VERSION 5.7 ;
  NOWIREEXTENSIONATPIN ON ;
  DIVIDERCHAR "/" ;
  BUSBITCHARS "[]" ;
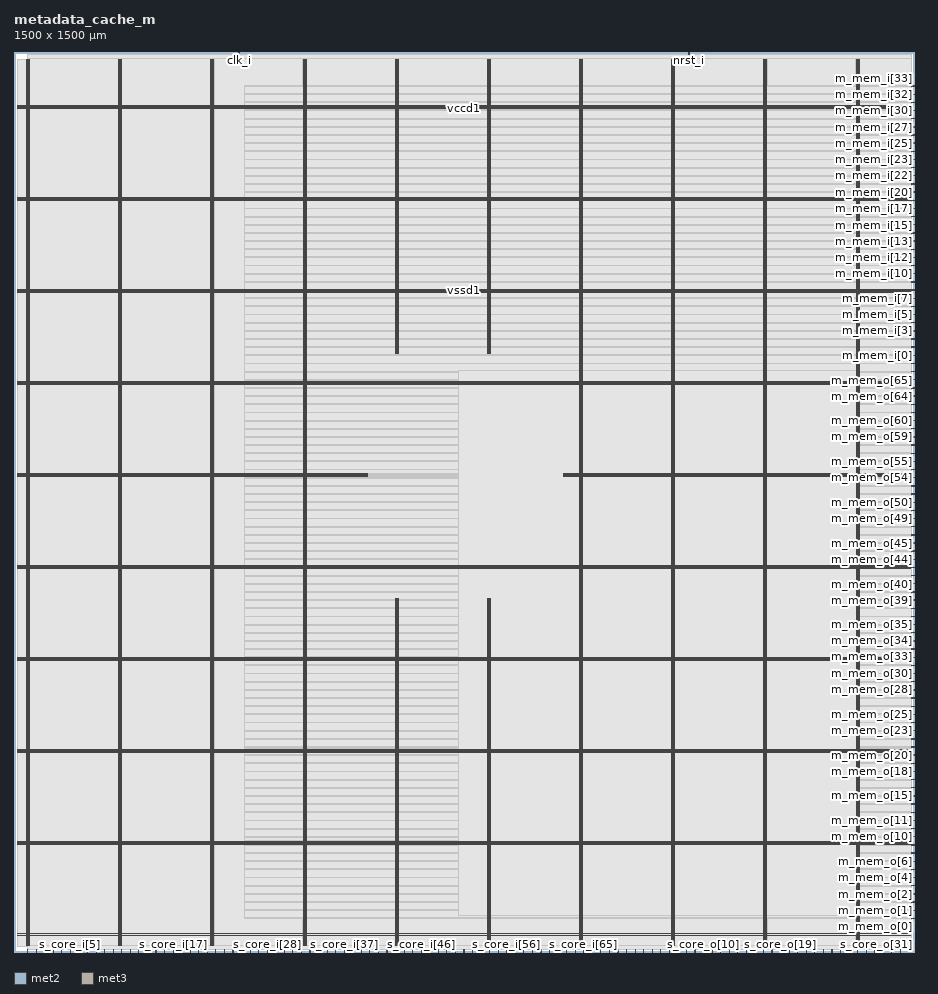
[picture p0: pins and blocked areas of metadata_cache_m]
MACRO metadata_cache_m
  CLASS BLOCK ;
  FOREIGN metadata_cache_m ;
  ORIGIN 0.000 0.000 ;
  SIZE 1500.000 BY 1500.000 ;
  PIN clk_i
    DIRECTION INPUT ;
    USE SIGNAL ;
    ANTENNAGATEAREA 0.990000 ;
    PORT
      LAYER met2 ;
        RECT 374.990 1496.000 375.270 1500.000 ;
    END
  END clk_i
  PIN m_mem_i[0]
    DIRECTION INPUT ;
    USE SIGNAL ;
    ANTENNAGATEAREA 0.742500 ;
    PORT
      LAYER met3 ;
        RECT 1496.000 994.200 1500.000 994.800 ;
    END
  END m_mem_i[0]
  PIN m_mem_i[10]
    DIRECTION INPUT ;
    USE SIGNAL ;
    ANTENNAGATEAREA 0.852000 ;
    PORT
      LAYER met3 ;
        RECT 1496.000 1130.200 1500.000 1130.800 ;
    END
  END m_mem_i[10]
  PIN m_mem_i[11]
    DIRECTION INPUT ;
    USE SIGNAL ;
    ANTENNAGATEAREA 0.990000 ;
    PORT
      LAYER met3 ;
        RECT 1496.000 1143.800 1500.000 1144.400 ;
    END
  END m_mem_i[11]
  PIN m_mem_i[12]
    DIRECTION INPUT ;
    USE SIGNAL ;
    ANTENNAGATEAREA 0.990000 ;
    PORT
      LAYER met3 ;
        RECT 1496.000 1157.400 1500.000 1158.000 ;
    END
  END m_mem_i[12]
  PIN m_mem_i[13]
    DIRECTION INPUT ;
    USE SIGNAL ;
    ANTENNAGATEAREA 0.990000 ;
    PORT
      LAYER met3 ;
        RECT 1496.000 1171.000 1500.000 1171.600 ;
    END
  END m_mem_i[13]
  PIN m_mem_i[14]
    DIRECTION INPUT ;
    USE SIGNAL ;
    ANTENNAGATEAREA 0.990000 ;
    PORT
      LAYER met3 ;
        RECT 1496.000 1184.600 1500.000 1185.200 ;
    END
  END m_mem_i[14]
  PIN m_mem_i[15]
    DIRECTION INPUT ;
    USE SIGNAL ;
    ANTENNAGATEAREA 0.990000 ;
    PORT
      LAYER met3 ;
        RECT 1496.000 1198.200 1500.000 1198.800 ;
    END
  END m_mem_i[15]
  PIN m_mem_i[16]
    DIRECTION INPUT ;
    USE SIGNAL ;
    ANTENNAGATEAREA 0.852000 ;
    PORT
      LAYER met3 ;
        RECT 1496.000 1211.800 1500.000 1212.400 ;
    END
  END m_mem_i[16]
  PIN m_mem_i[17]
    DIRECTION INPUT ;
    USE SIGNAL ;
    ANTENNAGATEAREA 0.742500 ;
    PORT
      LAYER met3 ;
        RECT 1496.000 1225.400 1500.000 1226.000 ;
    END
  END m_mem_i[17]
  PIN m_mem_i[18]
    DIRECTION INPUT ;
    USE SIGNAL ;
    ANTENNAGATEAREA 0.742500 ;
    PORT
      LAYER met3 ;
        RECT 1496.000 1239.000 1500.000 1239.600 ;
    END
  END m_mem_i[18]
  PIN m_mem_i[19]
    DIRECTION INPUT ;
    USE SIGNAL ;
    ANTENNAGATEAREA 0.742500 ;
    PORT
      LAYER met3 ;
        RECT 1496.000 1252.600 1500.000 1253.200 ;
    END
  END m_mem_i[19]
  PIN m_mem_i[1]
    DIRECTION INPUT ;
    USE SIGNAL ;
    ANTENNAGATEAREA 0.742500 ;
    PORT
      LAYER met3 ;
        RECT 1496.000 1007.800 1500.000 1008.400 ;
    END
  END m_mem_i[1]
  PIN m_mem_i[20]
    DIRECTION INPUT ;
    USE SIGNAL ;
    ANTENNAGATEAREA 0.742500 ;
    PORT
      LAYER met3 ;
        RECT 1496.000 1266.200 1500.000 1266.800 ;
    END
  END m_mem_i[20]
  PIN m_mem_i[21]
    DIRECTION INPUT ;
    USE SIGNAL ;
    ANTENNAGATEAREA 0.742500 ;
    PORT
      LAYER met3 ;
        RECT 1496.000 1279.800 1500.000 1280.400 ;
    END
  END m_mem_i[21]
  PIN m_mem_i[22]
    DIRECTION INPUT ;
    USE SIGNAL ;
    ANTENNAGATEAREA 0.742500 ;
    PORT
      LAYER met3 ;
        RECT 1496.000 1293.400 1500.000 1294.000 ;
    END
  END m_mem_i[22]
  PIN m_mem_i[23]
    DIRECTION INPUT ;
    USE SIGNAL ;
    ANTENNAGATEAREA 0.742500 ;
    PORT
      LAYER met3 ;
        RECT 1496.000 1307.000 1500.000 1307.600 ;
    END
  END m_mem_i[23]
  PIN m_mem_i[24]
    DIRECTION INPUT ;
    USE SIGNAL ;
    ANTENNAGATEAREA 0.852000 ;
    PORT
      LAYER met3 ;
        RECT 1496.000 1320.600 1500.000 1321.200 ;
    END
  END m_mem_i[24]
  PIN m_mem_i[25]
    DIRECTION INPUT ;
    USE SIGNAL ;
    ANTENNAGATEAREA 0.742500 ;
    PORT
      LAYER met3 ;
        RECT 1496.000 1334.200 1500.000 1334.800 ;
    END
  END m_mem_i[25]
  PIN m_mem_i[26]
    DIRECTION INPUT ;
    USE SIGNAL ;
    ANTENNAGATEAREA 0.742500 ;
    PORT
      LAYER met3 ;
        RECT 1496.000 1347.800 1500.000 1348.400 ;
    END
  END m_mem_i[26]
  PIN m_mem_i[27]
    DIRECTION INPUT ;
    USE SIGNAL ;
    ANTENNAGATEAREA 0.990000 ;
    PORT
      LAYER met3 ;
        RECT 1496.000 1361.400 1500.000 1362.000 ;
    END
  END m_mem_i[27]
  PIN m_mem_i[28]
    DIRECTION INPUT ;
    USE SIGNAL ;
    ANTENNAGATEAREA 0.852000 ;
    PORT
      LAYER met3 ;
        RECT 1496.000 1375.000 1500.000 1375.600 ;
    END
  END m_mem_i[28]
  PIN m_mem_i[29]
    DIRECTION INPUT ;
    USE SIGNAL ;
    ANTENNAGATEAREA 0.852000 ;
    PORT
      LAYER met3 ;
        RECT 1496.000 1388.600 1500.000 1389.200 ;
    END
  END m_mem_i[29]
  PIN m_mem_i[2]
    DIRECTION INPUT ;
    USE SIGNAL ;
    ANTENNAGATEAREA 0.742500 ;
    PORT
      LAYER met3 ;
        RECT 1496.000 1021.400 1500.000 1022.000 ;
    END
  END m_mem_i[2]
  PIN m_mem_i[30]
    DIRECTION INPUT ;
    USE SIGNAL ;
    ANTENNAGATEAREA 0.852000 ;
    PORT
      LAYER met3 ;
        RECT 1496.000 1402.200 1500.000 1402.800 ;
    END
  END m_mem_i[30]
  PIN m_mem_i[31]
    DIRECTION INPUT ;
    USE SIGNAL ;
    ANTENNAGATEAREA 0.852000 ;
    PORT
      LAYER met3 ;
        RECT 1496.000 1415.800 1500.000 1416.400 ;
    END
  END m_mem_i[31]
  PIN m_mem_i[32]
    DIRECTION INPUT ;
    USE SIGNAL ;
    ANTENNAGATEAREA 0.990000 ;
    PORT
      LAYER met3 ;
        RECT 1496.000 1429.400 1500.000 1430.000 ;
    END
  END m_mem_i[32]
  PIN m_mem_i[33]
    DIRECTION INPUT ;
    USE SIGNAL ;
    ANTENNAGATEAREA 0.990000 ;
    PORT
      LAYER met3 ;
        RECT 1496.000 1443.000 1500.000 1443.600 ;
    END
  END m_mem_i[33]
  PIN m_mem_i[3]
    DIRECTION INPUT ;
    USE SIGNAL ;
    ANTENNAGATEAREA 0.742500 ;
    PORT
      LAYER met3 ;
        RECT 1496.000 1035.000 1500.000 1035.600 ;
    END
  END m_mem_i[3]
  PIN m_mem_i[4]
    DIRECTION INPUT ;
    USE SIGNAL ;
    ANTENNAGATEAREA 0.742500 ;
    PORT
      LAYER met3 ;
        RECT 1496.000 1048.600 1500.000 1049.200 ;
    END
  END m_mem_i[4]
  PIN m_mem_i[5]
    DIRECTION INPUT ;
    USE SIGNAL ;
    ANTENNAGATEAREA 0.742500 ;
    PORT
      LAYER met3 ;
        RECT 1496.000 1062.200 1500.000 1062.800 ;
    END
  END m_mem_i[5]
  PIN m_mem_i[6]
    DIRECTION INPUT ;
    USE SIGNAL ;
    ANTENNAGATEAREA 0.742500 ;
    PORT
      LAYER met3 ;
        RECT 1496.000 1075.800 1500.000 1076.400 ;
    END
  END m_mem_i[6]
  PIN m_mem_i[7]
    DIRECTION INPUT ;
    USE SIGNAL ;
    ANTENNAGATEAREA 0.742500 ;
    PORT
      LAYER met3 ;
        RECT 1496.000 1089.400 1500.000 1090.000 ;
    END
  END m_mem_i[7]
  PIN m_mem_i[8]
    DIRECTION INPUT ;
    USE SIGNAL ;
    ANTENNAGATEAREA 0.742500 ;
    PORT
      LAYER met3 ;
        RECT 1496.000 1103.000 1500.000 1103.600 ;
    END
  END m_mem_i[8]
  PIN m_mem_i[9]
    DIRECTION INPUT ;
    USE SIGNAL ;
    ANTENNAGATEAREA 0.852000 ;
    PORT
      LAYER met3 ;
        RECT 1496.000 1116.600 1500.000 1117.200 ;
    END
  END m_mem_i[9]
  PIN m_mem_o[0]
    DIRECTION OUTPUT TRISTATE ;
    USE SIGNAL ;
    ANTENNADIFFAREA 2.673000 ;
    PORT
      LAYER met3 ;
        RECT 1496.000 55.800 1500.000 56.400 ;
    END
  END m_mem_o[0]
  PIN m_mem_o[10]
    DIRECTION OUTPUT TRISTATE ;
    USE SIGNAL ;
    ANTENNADIFFAREA 2.673000 ;
    PORT
      LAYER met3 ;
        RECT 1496.000 191.800 1500.000 192.400 ;
    END
  END m_mem_o[10]
  PIN m_mem_o[11]
    DIRECTION OUTPUT TRISTATE ;
    USE SIGNAL ;
    ANTENNADIFFAREA 2.673000 ;
    PORT
      LAYER met3 ;
        RECT 1496.000 205.400 1500.000 206.000 ;
    END
  END m_mem_o[11]
  PIN m_mem_o[12]
    DIRECTION OUTPUT TRISTATE ;
    USE SIGNAL ;
    ANTENNADIFFAREA 2.673000 ;
    PORT
      LAYER met3 ;
        RECT 1496.000 219.000 1500.000 219.600 ;
    END
  END m_mem_o[12]
  PIN m_mem_o[13]
    DIRECTION OUTPUT TRISTATE ;
    USE SIGNAL ;
    ANTENNADIFFAREA 2.673000 ;
    PORT
      LAYER met3 ;
        RECT 1496.000 232.600 1500.000 233.200 ;
    END
  END m_mem_o[13]
  PIN m_mem_o[14]
    DIRECTION OUTPUT TRISTATE ;
    USE SIGNAL ;
    ANTENNADIFFAREA 2.673000 ;
    PORT
      LAYER met3 ;
        RECT 1496.000 246.200 1500.000 246.800 ;
    END
  END m_mem_o[14]
  PIN m_mem_o[15]
    DIRECTION OUTPUT TRISTATE ;
    USE SIGNAL ;
    ANTENNADIFFAREA 2.673000 ;
    PORT
      LAYER met3 ;
        RECT 1496.000 259.800 1500.000 260.400 ;
    END
  END m_mem_o[15]
  PIN m_mem_o[16]
    DIRECTION OUTPUT TRISTATE ;
    USE SIGNAL ;
    ANTENNADIFFAREA 2.673000 ;
    PORT
      LAYER met3 ;
        RECT 1496.000 273.400 1500.000 274.000 ;
    END
  END m_mem_o[16]
  PIN m_mem_o[17]
    DIRECTION OUTPUT TRISTATE ;
    USE SIGNAL ;
    ANTENNADIFFAREA 2.673000 ;
    PORT
      LAYER met3 ;
        RECT 1496.000 287.000 1500.000 287.600 ;
    END
  END m_mem_o[17]
  PIN m_mem_o[18]
    DIRECTION OUTPUT TRISTATE ;
    USE SIGNAL ;
    ANTENNADIFFAREA 2.673000 ;
    PORT
      LAYER met3 ;
        RECT 1496.000 300.600 1500.000 301.200 ;
    END
  END m_mem_o[18]
  PIN m_mem_o[19]
    DIRECTION OUTPUT TRISTATE ;
    USE SIGNAL ;
    ANTENNADIFFAREA 2.673000 ;
    PORT
      LAYER met3 ;
        RECT 1496.000 314.200 1500.000 314.800 ;
    END
  END m_mem_o[19]
  PIN m_mem_o[1]
    DIRECTION OUTPUT TRISTATE ;
    USE SIGNAL ;
    ANTENNADIFFAREA 2.673000 ;
    PORT
      LAYER met3 ;
        RECT 1496.000 69.400 1500.000 70.000 ;
    END
  END m_mem_o[1]
  PIN m_mem_o[20]
    DIRECTION OUTPUT TRISTATE ;
    USE SIGNAL ;
    ANTENNADIFFAREA 2.673000 ;
    PORT
      LAYER met3 ;
        RECT 1496.000 327.800 1500.000 328.400 ;
    END
  END m_mem_o[20]
  PIN m_mem_o[21]
    DIRECTION OUTPUT TRISTATE ;
    USE SIGNAL ;
    ANTENNADIFFAREA 2.673000 ;
    PORT
      LAYER met3 ;
        RECT 1496.000 341.400 1500.000 342.000 ;
    END
  END m_mem_o[21]
  PIN m_mem_o[22]
    DIRECTION OUTPUT TRISTATE ;
    USE SIGNAL ;
    ANTENNADIFFAREA 2.673000 ;
    PORT
      LAYER met3 ;
        RECT 1496.000 355.000 1500.000 355.600 ;
    END
  END m_mem_o[22]
  PIN m_mem_o[23]
    DIRECTION OUTPUT TRISTATE ;
    USE SIGNAL ;
    ANTENNADIFFAREA 2.673000 ;
    PORT
      LAYER met3 ;
        RECT 1496.000 368.600 1500.000 369.200 ;
    END
  END m_mem_o[23]
  PIN m_mem_o[24]
    DIRECTION OUTPUT TRISTATE ;
    USE SIGNAL ;
    ANTENNADIFFAREA 2.673000 ;
    PORT
      LAYER met3 ;
        RECT 1496.000 382.200 1500.000 382.800 ;
    END
  END m_mem_o[24]
  PIN m_mem_o[25]
    DIRECTION OUTPUT TRISTATE ;
    USE SIGNAL ;
    ANTENNADIFFAREA 2.673000 ;
    PORT
      LAYER met3 ;
        RECT 1496.000 395.800 1500.000 396.400 ;
    END
  END m_mem_o[25]
  PIN m_mem_o[26]
    DIRECTION OUTPUT TRISTATE ;
    USE SIGNAL ;
    ANTENNADIFFAREA 2.673000 ;
    PORT
      LAYER met3 ;
        RECT 1496.000 409.400 1500.000 410.000 ;
    END
  END m_mem_o[26]
  PIN m_mem_o[27]
    DIRECTION OUTPUT TRISTATE ;
    USE SIGNAL ;
    ANTENNADIFFAREA 2.673000 ;
    PORT
      LAYER met3 ;
        RECT 1496.000 423.000 1500.000 423.600 ;
    END
  END m_mem_o[27]
  PIN m_mem_o[28]
    DIRECTION OUTPUT TRISTATE ;
    USE SIGNAL ;
    ANTENNADIFFAREA 2.673000 ;
    PORT
      LAYER met3 ;
        RECT 1496.000 436.600 1500.000 437.200 ;
    END
  END m_mem_o[28]
  PIN m_mem_o[29]
    DIRECTION OUTPUT TRISTATE ;
    USE SIGNAL ;
    ANTENNADIFFAREA 2.673000 ;
    PORT
      LAYER met3 ;
        RECT 1496.000 450.200 1500.000 450.800 ;
    END
  END m_mem_o[29]
  PIN m_mem_o[2]
    DIRECTION OUTPUT TRISTATE ;
    USE SIGNAL ;
    ANTENNADIFFAREA 2.673000 ;
    PORT
      LAYER met3 ;
        RECT 1496.000 83.000 1500.000 83.600 ;
    END
  END m_mem_o[2]
  PIN m_mem_o[30]
    DIRECTION OUTPUT TRISTATE ;
    USE SIGNAL ;
    ANTENNADIFFAREA 2.673000 ;
    PORT
      LAYER met3 ;
        RECT 1496.000 463.800 1500.000 464.400 ;
    END
  END m_mem_o[30]
  PIN m_mem_o[31]
    DIRECTION OUTPUT TRISTATE ;
    USE SIGNAL ;
    ANTENNADIFFAREA 2.673000 ;
    PORT
      LAYER met3 ;
        RECT 1496.000 477.400 1500.000 478.000 ;
    END
  END m_mem_o[31]
  PIN m_mem_o[32]
    DIRECTION OUTPUT TRISTATE ;
    USE SIGNAL ;
    PORT
      LAYER met3 ;
        RECT 1496.000 491.000 1500.000 491.600 ;
    END
  END m_mem_o[32]
  PIN m_mem_o[33]
    DIRECTION OUTPUT TRISTATE ;
    USE SIGNAL ;
    PORT
      LAYER met3 ;
        RECT 1496.000 504.600 1500.000 505.200 ;
    END
  END m_mem_o[33]
  PIN m_mem_o[34]
    DIRECTION OUTPUT TRISTATE ;
    USE SIGNAL ;
    PORT
      LAYER met3 ;
        RECT 1496.000 518.200 1500.000 518.800 ;
    END
  END m_mem_o[34]
  PIN m_mem_o[35]
    DIRECTION OUTPUT TRISTATE ;
    USE SIGNAL ;
    PORT
      LAYER met3 ;
        RECT 1496.000 531.800 1500.000 532.400 ;
    END
  END m_mem_o[35]
  PIN m_mem_o[36]
    DIRECTION OUTPUT TRISTATE ;
    USE SIGNAL ;
    PORT
      LAYER met3 ;
        RECT 1496.000 545.400 1500.000 546.000 ;
    END
  END m_mem_o[36]
  PIN m_mem_o[37]
    DIRECTION OUTPUT TRISTATE ;
    USE SIGNAL ;
    PORT
      LAYER met3 ;
        RECT 1496.000 559.000 1500.000 559.600 ;
    END
  END m_mem_o[37]
  PIN m_mem_o[38]
    DIRECTION OUTPUT TRISTATE ;
    USE SIGNAL ;
    ANTENNADIFFAREA 2.673000 ;
    PORT
      LAYER met3 ;
        RECT 1496.000 572.600 1500.000 573.200 ;
    END
  END m_mem_o[38]
  PIN m_mem_o[39]
    DIRECTION OUTPUT TRISTATE ;
    USE SIGNAL ;
    ANTENNADIFFAREA 2.673000 ;
    PORT
      LAYER met3 ;
        RECT 1496.000 586.200 1500.000 586.800 ;
    END
  END m_mem_o[39]
  PIN m_mem_o[3]
    DIRECTION OUTPUT TRISTATE ;
    USE SIGNAL ;
    ANTENNADIFFAREA 2.673000 ;
    PORT
      LAYER met3 ;
        RECT 1496.000 96.600 1500.000 97.200 ;
    END
  END m_mem_o[3]
  PIN m_mem_o[40]
    DIRECTION OUTPUT TRISTATE ;
    USE SIGNAL ;
    ANTENNADIFFAREA 2.673000 ;
    PORT
      LAYER met3 ;
        RECT 1496.000 599.800 1500.000 600.400 ;
    END
  END m_mem_o[40]
  PIN m_mem_o[41]
    DIRECTION OUTPUT TRISTATE ;
    USE SIGNAL ;
    ANTENNADIFFAREA 2.673000 ;
    PORT
      LAYER met3 ;
        RECT 1496.000 613.400 1500.000 614.000 ;
    END
  END m_mem_o[41]
  PIN m_mem_o[42]
    DIRECTION OUTPUT TRISTATE ;
    USE SIGNAL ;
    ANTENNADIFFAREA 2.673000 ;
    PORT
      LAYER met3 ;
        RECT 1496.000 627.000 1500.000 627.600 ;
    END
  END m_mem_o[42]
  PIN m_mem_o[43]
    DIRECTION OUTPUT TRISTATE ;
    USE SIGNAL ;
    ANTENNADIFFAREA 2.673000 ;
    PORT
      LAYER met3 ;
        RECT 1496.000 640.600 1500.000 641.200 ;
    END
  END m_mem_o[43]
  PIN m_mem_o[44]
    DIRECTION OUTPUT TRISTATE ;
    USE SIGNAL ;
    ANTENNADIFFAREA 2.673000 ;
    PORT
      LAYER met3 ;
        RECT 1496.000 654.200 1500.000 654.800 ;
    END
  END m_mem_o[44]
  PIN m_mem_o[45]
    DIRECTION OUTPUT TRISTATE ;
    USE SIGNAL ;
    ANTENNADIFFAREA 2.673000 ;
    PORT
      LAYER met3 ;
        RECT 1496.000 667.800 1500.000 668.400 ;
    END
  END m_mem_o[45]
  PIN m_mem_o[46]
    DIRECTION OUTPUT TRISTATE ;
    USE SIGNAL ;
    ANTENNADIFFAREA 2.673000 ;
    PORT
      LAYER met3 ;
        RECT 1496.000 681.400 1500.000 682.000 ;
    END
  END m_mem_o[46]
  PIN m_mem_o[47]
    DIRECTION OUTPUT TRISTATE ;
    USE SIGNAL ;
    ANTENNADIFFAREA 2.673000 ;
    PORT
      LAYER met3 ;
        RECT 1496.000 695.000 1500.000 695.600 ;
    END
  END m_mem_o[47]
  PIN m_mem_o[48]
    DIRECTION OUTPUT TRISTATE ;
    USE SIGNAL ;
    ANTENNADIFFAREA 2.673000 ;
    PORT
      LAYER met3 ;
        RECT 1496.000 708.600 1500.000 709.200 ;
    END
  END m_mem_o[48]
  PIN m_mem_o[49]
    DIRECTION OUTPUT TRISTATE ;
    USE SIGNAL ;
    ANTENNADIFFAREA 2.673000 ;
    PORT
      LAYER met3 ;
        RECT 1496.000 722.200 1500.000 722.800 ;
    END
  END m_mem_o[49]
  PIN m_mem_o[4]
    DIRECTION OUTPUT TRISTATE ;
    USE SIGNAL ;
    ANTENNADIFFAREA 2.673000 ;
    PORT
      LAYER met3 ;
        RECT 1496.000 110.200 1500.000 110.800 ;
    END
  END m_mem_o[4]
  PIN m_mem_o[50]
    DIRECTION OUTPUT TRISTATE ;
    USE SIGNAL ;
    ANTENNADIFFAREA 2.673000 ;
    PORT
      LAYER met3 ;
        RECT 1496.000 735.800 1500.000 736.400 ;
    END
  END m_mem_o[50]
  PIN m_mem_o[51]
    DIRECTION OUTPUT TRISTATE ;
    USE SIGNAL ;
    ANTENNADIFFAREA 2.673000 ;
    PORT
      LAYER met3 ;
        RECT 1496.000 749.400 1500.000 750.000 ;
    END
  END m_mem_o[51]
  PIN m_mem_o[52]
    DIRECTION OUTPUT TRISTATE ;
    USE SIGNAL ;
    ANTENNADIFFAREA 2.673000 ;
    PORT
      LAYER met3 ;
        RECT 1496.000 763.000 1500.000 763.600 ;
    END
  END m_mem_o[52]
  PIN m_mem_o[53]
    DIRECTION OUTPUT TRISTATE ;
    USE SIGNAL ;
    ANTENNADIFFAREA 2.673000 ;
    PORT
      LAYER met3 ;
        RECT 1496.000 776.600 1500.000 777.200 ;
    END
  END m_mem_o[53]
  PIN m_mem_o[54]
    DIRECTION OUTPUT TRISTATE ;
    USE SIGNAL ;
    ANTENNADIFFAREA 2.673000 ;
    PORT
      LAYER met3 ;
        RECT 1496.000 790.200 1500.000 790.800 ;
    END
  END m_mem_o[54]
  PIN m_mem_o[55]
    DIRECTION OUTPUT TRISTATE ;
    USE SIGNAL ;
    ANTENNADIFFAREA 2.673000 ;
    PORT
      LAYER met3 ;
        RECT 1496.000 803.800 1500.000 804.400 ;
    END
  END m_mem_o[55]
  PIN m_mem_o[56]
    DIRECTION OUTPUT TRISTATE ;
    USE SIGNAL ;
    ANTENNADIFFAREA 2.673000 ;
    PORT
      LAYER met3 ;
        RECT 1496.000 817.400 1500.000 818.000 ;
    END
  END m_mem_o[56]
  PIN m_mem_o[57]
    DIRECTION OUTPUT TRISTATE ;
    USE SIGNAL ;
    ANTENNADIFFAREA 2.673000 ;
    PORT
      LAYER met3 ;
        RECT 1496.000 831.000 1500.000 831.600 ;
    END
  END m_mem_o[57]
  PIN m_mem_o[58]
    DIRECTION OUTPUT TRISTATE ;
    USE SIGNAL ;
    ANTENNADIFFAREA 2.673000 ;
    PORT
      LAYER met3 ;
        RECT 1496.000 844.600 1500.000 845.200 ;
    END
  END m_mem_o[58]
  PIN m_mem_o[59]
    DIRECTION OUTPUT TRISTATE ;
    USE SIGNAL ;
    ANTENNADIFFAREA 2.673000 ;
    PORT
      LAYER met3 ;
        RECT 1496.000 858.200 1500.000 858.800 ;
    END
  END m_mem_o[59]
  PIN m_mem_o[5]
    DIRECTION OUTPUT TRISTATE ;
    USE SIGNAL ;
    ANTENNADIFFAREA 2.673000 ;
    PORT
      LAYER met3 ;
        RECT 1496.000 123.800 1500.000 124.400 ;
    END
  END m_mem_o[5]
  PIN m_mem_o[60]
    DIRECTION OUTPUT TRISTATE ;
    USE SIGNAL ;
    ANTENNADIFFAREA 2.673000 ;
    PORT
      LAYER met3 ;
        RECT 1496.000 871.800 1500.000 872.400 ;
    END
  END m_mem_o[60]
  PIN m_mem_o[61]
    DIRECTION OUTPUT TRISTATE ;
    USE SIGNAL ;
    ANTENNADIFFAREA 2.673000 ;
    PORT
      LAYER met3 ;
        RECT 1496.000 885.400 1500.000 886.000 ;
    END
  END m_mem_o[61]
  PIN m_mem_o[62]
    DIRECTION OUTPUT TRISTATE ;
    USE SIGNAL ;
    ANTENNADIFFAREA 2.673000 ;
    PORT
      LAYER met3 ;
        RECT 1496.000 899.000 1500.000 899.600 ;
    END
  END m_mem_o[62]
  PIN m_mem_o[63]
    DIRECTION OUTPUT TRISTATE ;
    USE SIGNAL ;
    ANTENNADIFFAREA 2.673000 ;
    PORT
      LAYER met3 ;
        RECT 1496.000 912.600 1500.000 913.200 ;
    END
  END m_mem_o[63]
  PIN m_mem_o[64]
    DIRECTION OUTPUT TRISTATE ;
    USE SIGNAL ;
    ANTENNADIFFAREA 2.673000 ;
    PORT
      LAYER met3 ;
        RECT 1496.000 926.200 1500.000 926.800 ;
    END
  END m_mem_o[64]
  PIN m_mem_o[65]
    DIRECTION OUTPUT TRISTATE ;
    USE SIGNAL ;
    ANTENNADIFFAREA 2.673000 ;
    PORT
      LAYER met3 ;
        RECT 1496.000 939.800 1500.000 940.400 ;
    END
  END m_mem_o[65]
  PIN m_mem_o[66]
    DIRECTION OUTPUT TRISTATE ;
    USE SIGNAL ;
    PORT
      LAYER met3 ;
        RECT 1496.000 953.400 1500.000 954.000 ;
    END
  END m_mem_o[66]
  PIN m_mem_o[67]
    DIRECTION OUTPUT TRISTATE ;
    USE SIGNAL ;
    PORT
      LAYER met3 ;
        RECT 1496.000 967.000 1500.000 967.600 ;
    END
  END m_mem_o[67]
  PIN m_mem_o[68]
    DIRECTION OUTPUT TRISTATE ;
    USE SIGNAL ;
    ANTENNADIFFAREA 2.673000 ;
    PORT
      LAYER met3 ;
        RECT 1496.000 980.600 1500.000 981.200 ;
    END
  END m_mem_o[68]
  PIN m_mem_o[6]
    DIRECTION OUTPUT TRISTATE ;
    USE SIGNAL ;
    ANTENNADIFFAREA 2.673000 ;
    PORT
      LAYER met3 ;
        RECT 1496.000 137.400 1500.000 138.000 ;
    END
  END m_mem_o[6]
  PIN m_mem_o[7]
    DIRECTION OUTPUT TRISTATE ;
    USE SIGNAL ;
    ANTENNADIFFAREA 2.673000 ;
    PORT
      LAYER met3 ;
        RECT 1496.000 151.000 1500.000 151.600 ;
    END
  END m_mem_o[7]
  PIN m_mem_o[8]
    DIRECTION OUTPUT TRISTATE ;
    USE SIGNAL ;
    ANTENNADIFFAREA 2.673000 ;
    PORT
      LAYER met3 ;
        RECT 1496.000 164.600 1500.000 165.200 ;
    END
  END m_mem_o[8]
  PIN m_mem_o[9]
    DIRECTION OUTPUT TRISTATE ;
    USE SIGNAL ;
    ANTENNADIFFAREA 2.673000 ;
    PORT
      LAYER met3 ;
        RECT 1496.000 178.200 1500.000 178.800 ;
    END
  END m_mem_o[9]
  PIN nrst_i
    DIRECTION INPUT ;
    USE SIGNAL ;
    ANTENNAGATEAREA 0.990000 ;
    PORT
      LAYER met2 ;
        RECT 1124.790 1496.000 1125.070 1500.000 ;
    END
  END nrst_i
  PIN s_core_i[0]
    DIRECTION INPUT ;
    USE SIGNAL ;
    ANTENNAGATEAREA 0.742500 ;
    PORT
      LAYER met2 ;
        RECT 22.630 0.000 22.910 4.000 ;
    END
  END s_core_i[0]
  PIN s_core_i[10]
    DIRECTION INPUT ;
    USE SIGNAL ;
    ANTENNAGATEAREA 0.247500 ;
    PORT
      LAYER met2 ;
        RECT 165.230 0.000 165.510 4.000 ;
    END
  END s_core_i[10]
  PIN s_core_i[11]
    DIRECTION INPUT ;
    USE SIGNAL ;
    ANTENNAGATEAREA 0.247500 ;
    PORT
      LAYER met2 ;
        RECT 179.490 0.000 179.770 4.000 ;
    END
  END s_core_i[11]
  PIN s_core_i[12]
    DIRECTION INPUT ;
    USE SIGNAL ;
    ANTENNAGATEAREA 0.247500 ;
    PORT
      LAYER met2 ;
        RECT 193.750 0.000 194.030 4.000 ;
    END
  END s_core_i[12]
  PIN s_core_i[13]
    DIRECTION INPUT ;
    USE SIGNAL ;
    ANTENNAGATEAREA 0.247500 ;
    PORT
      LAYER met2 ;
        RECT 208.010 0.000 208.290 4.000 ;
    END
  END s_core_i[13]
  PIN s_core_i[14]
    DIRECTION INPUT ;
    USE SIGNAL ;
    ANTENNAGATEAREA 0.247500 ;
    PORT
      LAYER met2 ;
        RECT 222.270 0.000 222.550 4.000 ;
    END
  END s_core_i[14]
  PIN s_core_i[15]
    DIRECTION INPUT ;
    USE SIGNAL ;
    ANTENNAGATEAREA 0.247500 ;
    PORT
      LAYER met2 ;
        RECT 236.530 0.000 236.810 4.000 ;
    END
  END s_core_i[15]
  PIN s_core_i[16]
    DIRECTION INPUT ;
    USE SIGNAL ;
    ANTENNAGATEAREA 0.247500 ;
    PORT
      LAYER met2 ;
        RECT 250.790 0.000 251.070 4.000 ;
    END
  END s_core_i[16]
  PIN s_core_i[17]
    DIRECTION INPUT ;
    USE SIGNAL ;
    ANTENNAGATEAREA 0.247500 ;
    PORT
      LAYER met2 ;
        RECT 265.050 0.000 265.330 4.000 ;
    END
  END s_core_i[17]
  PIN s_core_i[18]
    DIRECTION INPUT ;
    USE SIGNAL ;
    ANTENNAGATEAREA 0.247500 ;
    PORT
      LAYER met2 ;
        RECT 279.310 0.000 279.590 4.000 ;
    END
  END s_core_i[18]
  PIN s_core_i[19]
    DIRECTION INPUT ;
    USE SIGNAL ;
    ANTENNAGATEAREA 0.247500 ;
    PORT
      LAYER met2 ;
        RECT 293.570 0.000 293.850 4.000 ;
    END
  END s_core_i[19]
  PIN s_core_i[1]
    DIRECTION INPUT ;
    USE SIGNAL ;
    ANTENNAGATEAREA 0.742500 ;
    PORT
      LAYER met2 ;
        RECT 36.890 0.000 37.170 4.000 ;
    END
  END s_core_i[1]
  PIN s_core_i[20]
    DIRECTION INPUT ;
    USE SIGNAL ;
    ANTENNAGATEAREA 0.247500 ;
    PORT
      LAYER met2 ;
        RECT 307.830 0.000 308.110 4.000 ;
    END
  END s_core_i[20]
  PIN s_core_i[21]
    DIRECTION INPUT ;
    USE SIGNAL ;
    ANTENNAGATEAREA 0.247500 ;
    PORT
      LAYER met2 ;
        RECT 322.090 0.000 322.370 4.000 ;
    END
  END s_core_i[21]
  PIN s_core_i[22]
    DIRECTION INPUT ;
    USE SIGNAL ;
    ANTENNAGATEAREA 0.247500 ;
    PORT
      LAYER met2 ;
        RECT 336.350 0.000 336.630 4.000 ;
    END
  END s_core_i[22]
  PIN s_core_i[23]
    DIRECTION INPUT ;
    USE SIGNAL ;
    ANTENNAGATEAREA 0.247500 ;
    PORT
      LAYER met2 ;
        RECT 350.610 0.000 350.890 4.000 ;
    END
  END s_core_i[23]
  PIN s_core_i[24]
    DIRECTION INPUT ;
    USE SIGNAL ;
    ANTENNAGATEAREA 0.213000 ;
    PORT
      LAYER met2 ;
        RECT 364.870 0.000 365.150 4.000 ;
    END
  END s_core_i[24]
  PIN s_core_i[25]
    DIRECTION INPUT ;
    USE SIGNAL ;
    ANTENNAGATEAREA 0.247500 ;
    PORT
      LAYER met2 ;
        RECT 379.130 0.000 379.410 4.000 ;
    END
  END s_core_i[25]
  PIN s_core_i[26]
    DIRECTION INPUT ;
    USE SIGNAL ;
    ANTENNAGATEAREA 0.247500 ;
    PORT
      LAYER met2 ;
        RECT 393.390 0.000 393.670 4.000 ;
    END
  END s_core_i[26]
  PIN s_core_i[27]
    DIRECTION INPUT ;
    USE SIGNAL ;
    ANTENNAGATEAREA 0.247500 ;
    PORT
      LAYER met2 ;
        RECT 407.650 0.000 407.930 4.000 ;
    END
  END s_core_i[27]
  PIN s_core_i[28]
    DIRECTION INPUT ;
    USE SIGNAL ;
    ANTENNAGATEAREA 0.247500 ;
    PORT
      LAYER met2 ;
        RECT 421.910 0.000 422.190 4.000 ;
    END
  END s_core_i[28]
  PIN s_core_i[29]
    DIRECTION INPUT ;
    USE SIGNAL ;
    ANTENNAGATEAREA 0.213000 ;
    PORT
      LAYER met2 ;
        RECT 436.170 0.000 436.450 4.000 ;
    END
  END s_core_i[29]
  PIN s_core_i[2]
    DIRECTION INPUT ;
    USE SIGNAL ;
    ANTENNAGATEAREA 0.742500 ;
    PORT
      LAYER met2 ;
        RECT 51.150 0.000 51.430 4.000 ;
    END
  END s_core_i[2]
  PIN s_core_i[30]
    DIRECTION INPUT ;
    USE SIGNAL ;
    ANTENNAGATEAREA 0.213000 ;
    PORT
      LAYER met2 ;
        RECT 450.430 0.000 450.710 4.000 ;
    END
  END s_core_i[30]
  PIN s_core_i[31]
    DIRECTION INPUT ;
    USE SIGNAL ;
    ANTENNAGATEAREA 0.213000 ;
    PORT
      LAYER met2 ;
        RECT 464.690 0.000 464.970 4.000 ;
    END
  END s_core_i[31]
  PIN s_core_i[32]
    DIRECTION INPUT ;
    USE SIGNAL ;
    PORT
      LAYER met2 ;
        RECT 478.950 0.000 479.230 4.000 ;
    END
  END s_core_i[32]
  PIN s_core_i[33]
    DIRECTION INPUT ;
    USE SIGNAL ;
    PORT
      LAYER met2 ;
        RECT 493.210 0.000 493.490 4.000 ;
    END
  END s_core_i[33]
  PIN s_core_i[34]
    DIRECTION INPUT ;
    USE SIGNAL ;
    ANTENNAGATEAREA 0.426000 ;
    PORT
      LAYER met2 ;
        RECT 507.470 0.000 507.750 4.000 ;
    END
  END s_core_i[34]
  PIN s_core_i[35]
    DIRECTION INPUT ;
    USE SIGNAL ;
    ANTENNAGATEAREA 0.426000 ;
    PORT
      LAYER met2 ;
        RECT 521.730 0.000 522.010 4.000 ;
    END
  END s_core_i[35]
  PIN s_core_i[36]
    DIRECTION INPUT ;
    USE SIGNAL ;
    ANTENNAGATEAREA 0.426000 ;
    PORT
      LAYER met2 ;
        RECT 535.990 0.000 536.270 4.000 ;
    END
  END s_core_i[36]
  PIN s_core_i[37]
    DIRECTION INPUT ;
    USE SIGNAL ;
    ANTENNAGATEAREA 0.247500 ;
    PORT
      LAYER met2 ;
        RECT 550.250 0.000 550.530 4.000 ;
    END
  END s_core_i[37]
  PIN s_core_i[38]
    DIRECTION INPUT ;
    USE SIGNAL ;
    ANTENNAGATEAREA 0.426000 ;
    PORT
      LAYER met2 ;
        RECT 564.510 0.000 564.790 4.000 ;
    END
  END s_core_i[38]
  PIN s_core_i[39]
    DIRECTION INPUT ;
    USE SIGNAL ;
    ANTENNAGATEAREA 0.426000 ;
    PORT
      LAYER met2 ;
        RECT 578.770 0.000 579.050 4.000 ;
    END
  END s_core_i[39]
  PIN s_core_i[3]
    DIRECTION INPUT ;
    USE SIGNAL ;
    ANTENNAGATEAREA 0.742500 ;
    PORT
      LAYER met2 ;
        RECT 65.410 0.000 65.690 4.000 ;
    END
  END s_core_i[3]
  PIN s_core_i[40]
    DIRECTION INPUT ;
    USE SIGNAL ;
    ANTENNAGATEAREA 0.426000 ;
    PORT
      LAYER met2 ;
        RECT 593.030 0.000 593.310 4.000 ;
    END
  END s_core_i[40]
  PIN s_core_i[41]
    DIRECTION INPUT ;
    USE SIGNAL ;
    ANTENNAGATEAREA 0.426000 ;
    PORT
      LAYER met2 ;
        RECT 607.290 0.000 607.570 4.000 ;
    END
  END s_core_i[41]
  PIN s_core_i[42]
    DIRECTION INPUT ;
    USE SIGNAL ;
    ANTENNAGATEAREA 0.426000 ;
    PORT
      LAYER met2 ;
        RECT 621.550 0.000 621.830 4.000 ;
    END
  END s_core_i[42]
  PIN s_core_i[43]
    DIRECTION INPUT ;
    USE SIGNAL ;
    ANTENNAGATEAREA 0.426000 ;
    PORT
      LAYER met2 ;
        RECT 635.810 0.000 636.090 4.000 ;
    END
  END s_core_i[43]
  PIN s_core_i[44]
    DIRECTION INPUT ;
    USE SIGNAL ;
    ANTENNAGATEAREA 0.159000 ;
    PORT
      LAYER met2 ;
        RECT 650.070 0.000 650.350 4.000 ;
    END
  END s_core_i[44]
  PIN s_core_i[45]
    DIRECTION INPUT ;
    USE SIGNAL ;
    ANTENNAGATEAREA 0.159000 ;
    PORT
      LAYER met2 ;
        RECT 664.330 0.000 664.610 4.000 ;
    END
  END s_core_i[45]
  PIN s_core_i[46]
    DIRECTION INPUT ;
    USE SIGNAL ;
    ANTENNAGATEAREA 0.159000 ;
    PORT
      LAYER met2 ;
        RECT 678.590 0.000 678.870 4.000 ;
    END
  END s_core_i[46]
  PIN s_core_i[47]
    DIRECTION INPUT ;
    USE SIGNAL ;
    ANTENNAGATEAREA 0.159000 ;
    PORT
      LAYER met2 ;
        RECT 692.850 0.000 693.130 4.000 ;
    END
  END s_core_i[47]
  PIN s_core_i[48]
    DIRECTION INPUT ;
    USE SIGNAL ;
    ANTENNAGATEAREA 0.213000 ;
    PORT
      LAYER met2 ;
        RECT 707.110 0.000 707.390 4.000 ;
    END
  END s_core_i[48]
  PIN s_core_i[49]
    DIRECTION INPUT ;
    USE SIGNAL ;
    ANTENNAGATEAREA 0.213000 ;
    PORT
      LAYER met2 ;
        RECT 721.370 0.000 721.650 4.000 ;
    END
  END s_core_i[49]
  PIN s_core_i[4]
    DIRECTION INPUT ;
    USE SIGNAL ;
    ANTENNAGATEAREA 0.742500 ;
    PORT
      LAYER met2 ;
        RECT 79.670 0.000 79.950 4.000 ;
    END
  END s_core_i[4]
  PIN s_core_i[50]
    DIRECTION INPUT ;
    USE SIGNAL ;
    ANTENNAGATEAREA 0.213000 ;
    PORT
      LAYER met2 ;
        RECT 735.630 0.000 735.910 4.000 ;
    END
  END s_core_i[50]
  PIN s_core_i[51]
    DIRECTION INPUT ;
    USE SIGNAL ;
    ANTENNAGATEAREA 0.159000 ;
    PORT
      LAYER met2 ;
        RECT 749.890 0.000 750.170 4.000 ;
    END
  END s_core_i[51]
  PIN s_core_i[52]
    DIRECTION INPUT ;
    USE SIGNAL ;
    ANTENNAGATEAREA 0.213000 ;
    PORT
      LAYER met2 ;
        RECT 764.150 0.000 764.430 4.000 ;
    END
  END s_core_i[52]
  PIN s_core_i[53]
    DIRECTION INPUT ;
    USE SIGNAL ;
    ANTENNAGATEAREA 0.213000 ;
    PORT
      LAYER met2 ;
        RECT 778.410 0.000 778.690 4.000 ;
    END
  END s_core_i[53]
  PIN s_core_i[54]
    DIRECTION INPUT ;
    USE SIGNAL ;
    ANTENNAGATEAREA 0.213000 ;
    PORT
      LAYER met2 ;
        RECT 792.670 0.000 792.950 4.000 ;
    END
  END s_core_i[54]
  PIN s_core_i[55]
    DIRECTION INPUT ;
    USE SIGNAL ;
    ANTENNAGATEAREA 0.213000 ;
    PORT
      LAYER met2 ;
        RECT 806.930 0.000 807.210 4.000 ;
    END
  END s_core_i[55]
  PIN s_core_i[56]
    DIRECTION INPUT ;
    USE SIGNAL ;
    ANTENNAGATEAREA 0.213000 ;
    PORT
      LAYER met2 ;
        RECT 821.190 0.000 821.470 4.000 ;
    END
  END s_core_i[56]
  PIN s_core_i[57]
    DIRECTION INPUT ;
    USE SIGNAL ;
    ANTENNAGATEAREA 0.213000 ;
    PORT
      LAYER met2 ;
        RECT 835.450 0.000 835.730 4.000 ;
    END
  END s_core_i[57]
  PIN s_core_i[58]
    DIRECTION INPUT ;
    USE SIGNAL ;
    ANTENNAGATEAREA 0.213000 ;
    PORT
      LAYER met2 ;
        RECT 849.710 0.000 849.990 4.000 ;
    END
  END s_core_i[58]
  PIN s_core_i[59]
    DIRECTION INPUT ;
    USE SIGNAL ;
    ANTENNAGATEAREA 0.213000 ;
    PORT
      LAYER met2 ;
        RECT 863.970 0.000 864.250 4.000 ;
    END
  END s_core_i[59]
  PIN s_core_i[5]
    DIRECTION INPUT ;
    USE SIGNAL ;
    ANTENNAGATEAREA 0.426000 ;
    PORT
      LAYER met2 ;
        RECT 93.930 0.000 94.210 4.000 ;
    END
  END s_core_i[5]
  PIN s_core_i[60]
    DIRECTION INPUT ;
    USE SIGNAL ;
    ANTENNAGATEAREA 0.213000 ;
    PORT
      LAYER met2 ;
        RECT 878.230 0.000 878.510 4.000 ;
    END
  END s_core_i[60]
  PIN s_core_i[61]
    DIRECTION INPUT ;
    USE SIGNAL ;
    ANTENNAGATEAREA 0.213000 ;
    PORT
      LAYER met2 ;
        RECT 892.490 0.000 892.770 4.000 ;
    END
  END s_core_i[61]
  PIN s_core_i[62]
    DIRECTION INPUT ;
    USE SIGNAL ;
    ANTENNAGATEAREA 0.213000 ;
    PORT
      LAYER met2 ;
        RECT 906.750 0.000 907.030 4.000 ;
    END
  END s_core_i[62]
  PIN s_core_i[63]
    DIRECTION INPUT ;
    USE SIGNAL ;
    ANTENNAGATEAREA 0.213000 ;
    PORT
      LAYER met2 ;
        RECT 921.010 0.000 921.290 4.000 ;
    END
  END s_core_i[63]
  PIN s_core_i[64]
    DIRECTION INPUT ;
    USE SIGNAL ;
    ANTENNAGATEAREA 0.247500 ;
    PORT
      LAYER met2 ;
        RECT 935.270 0.000 935.550 4.000 ;
    END
  END s_core_i[64]
  PIN s_core_i[65]
    DIRECTION INPUT ;
    USE SIGNAL ;
    PORT
      LAYER met2 ;
        RECT 949.530 0.000 949.810 4.000 ;
    END
  END s_core_i[65]
  PIN s_core_i[66]
    DIRECTION INPUT ;
    USE SIGNAL ;
    PORT
      LAYER met2 ;
        RECT 963.790 0.000 964.070 4.000 ;
    END
  END s_core_i[66]
  PIN s_core_i[67]
    DIRECTION INPUT ;
    USE SIGNAL ;
    PORT
      LAYER met2 ;
        RECT 978.050 0.000 978.330 4.000 ;
    END
  END s_core_i[67]
  PIN s_core_i[68]
    DIRECTION INPUT ;
    USE SIGNAL ;
    ANTENNAGATEAREA 0.159000 ;
    PORT
      LAYER met2 ;
        RECT 992.310 0.000 992.590 4.000 ;
    END
  END s_core_i[68]
  PIN s_core_i[6]
    DIRECTION INPUT ;
    USE SIGNAL ;
    ANTENNAGATEAREA 0.247500 ;
    PORT
      LAYER met2 ;
        RECT 108.190 0.000 108.470 4.000 ;
    END
  END s_core_i[6]
  PIN s_core_i[7]
    DIRECTION INPUT ;
    USE SIGNAL ;
    ANTENNAGATEAREA 0.247500 ;
    PORT
      LAYER met2 ;
        RECT 122.450 0.000 122.730 4.000 ;
    END
  END s_core_i[7]
  PIN s_core_i[8]
    DIRECTION INPUT ;
    USE SIGNAL ;
    ANTENNAGATEAREA 0.247500 ;
    PORT
      LAYER met2 ;
        RECT 136.710 0.000 136.990 4.000 ;
    END
  END s_core_i[8]
  PIN s_core_i[9]
    DIRECTION INPUT ;
    USE SIGNAL ;
    ANTENNAGATEAREA 0.247500 ;
    PORT
      LAYER met2 ;
        RECT 150.970 0.000 151.250 4.000 ;
    END
  END s_core_i[9]
  PIN s_core_o[0]
    DIRECTION OUTPUT TRISTATE ;
    USE SIGNAL ;
    ANTENNADIFFAREA 2.673000 ;
    PORT
      LAYER met2 ;
        RECT 1006.570 0.000 1006.850 4.000 ;
    END
  END s_core_o[0]
  PIN s_core_o[10]
    DIRECTION OUTPUT TRISTATE ;
    USE SIGNAL ;
    ANTENNADIFFAREA 2.673000 ;
    PORT
      LAYER met2 ;
        RECT 1149.170 0.000 1149.450 4.000 ;
    END
  END s_core_o[10]
  PIN s_core_o[11]
    DIRECTION OUTPUT TRISTATE ;
    USE SIGNAL ;
    ANTENNADIFFAREA 2.673000 ;
    PORT
      LAYER met2 ;
        RECT 1163.430 0.000 1163.710 4.000 ;
    END
  END s_core_o[11]
  PIN s_core_o[12]
    DIRECTION OUTPUT TRISTATE ;
    USE SIGNAL ;
    ANTENNADIFFAREA 2.673000 ;
    PORT
      LAYER met2 ;
        RECT 1177.690 0.000 1177.970 4.000 ;
    END
  END s_core_o[12]
  PIN s_core_o[13]
    DIRECTION OUTPUT TRISTATE ;
    USE SIGNAL ;
    ANTENNADIFFAREA 2.673000 ;
    PORT
      LAYER met2 ;
        RECT 1191.950 0.000 1192.230 4.000 ;
    END
  END s_core_o[13]
  PIN s_core_o[14]
    DIRECTION OUTPUT TRISTATE ;
    USE SIGNAL ;
    ANTENNADIFFAREA 2.673000 ;
    PORT
      LAYER met2 ;
        RECT 1206.210 0.000 1206.490 4.000 ;
    END
  END s_core_o[14]
  PIN s_core_o[15]
    DIRECTION OUTPUT TRISTATE ;
    USE SIGNAL ;
    ANTENNADIFFAREA 2.673000 ;
    PORT
      LAYER met2 ;
        RECT 1220.470 0.000 1220.750 4.000 ;
    END
  END s_core_o[15]
  PIN s_core_o[16]
    DIRECTION OUTPUT TRISTATE ;
    USE SIGNAL ;
    ANTENNADIFFAREA 2.673000 ;
    PORT
      LAYER met2 ;
        RECT 1234.730 0.000 1235.010 4.000 ;
    END
  END s_core_o[16]
  PIN s_core_o[17]
    DIRECTION OUTPUT TRISTATE ;
    USE SIGNAL ;
    ANTENNADIFFAREA 2.673000 ;
    PORT
      LAYER met2 ;
        RECT 1248.990 0.000 1249.270 4.000 ;
    END
  END s_core_o[17]
  PIN s_core_o[18]
    DIRECTION OUTPUT TRISTATE ;
    USE SIGNAL ;
    ANTENNADIFFAREA 2.673000 ;
    PORT
      LAYER met2 ;
        RECT 1263.250 0.000 1263.530 4.000 ;
    END
  END s_core_o[18]
  PIN s_core_o[19]
    DIRECTION OUTPUT TRISTATE ;
    USE SIGNAL ;
    ANTENNADIFFAREA 2.673000 ;
    PORT
      LAYER met2 ;
        RECT 1277.510 0.000 1277.790 4.000 ;
    END
  END s_core_o[19]
  PIN s_core_o[1]
    DIRECTION OUTPUT TRISTATE ;
    USE SIGNAL ;
    ANTENNADIFFAREA 2.673000 ;
    PORT
      LAYER met2 ;
        RECT 1020.830 0.000 1021.110 4.000 ;
    END
  END s_core_o[1]
  PIN s_core_o[20]
    DIRECTION OUTPUT TRISTATE ;
    USE SIGNAL ;
    ANTENNADIFFAREA 2.673000 ;
    PORT
      LAYER met2 ;
        RECT 1291.770 0.000 1292.050 4.000 ;
    END
  END s_core_o[20]
  PIN s_core_o[21]
    DIRECTION OUTPUT TRISTATE ;
    USE SIGNAL ;
    ANTENNADIFFAREA 2.673000 ;
    PORT
      LAYER met2 ;
        RECT 1306.030 0.000 1306.310 4.000 ;
    END
  END s_core_o[21]
  PIN s_core_o[22]
    DIRECTION OUTPUT TRISTATE ;
    USE SIGNAL ;
    ANTENNADIFFAREA 2.673000 ;
    PORT
      LAYER met2 ;
        RECT 1320.290 0.000 1320.570 4.000 ;
    END
  END s_core_o[22]
  PIN s_core_o[23]
    DIRECTION OUTPUT TRISTATE ;
    USE SIGNAL ;
    ANTENNADIFFAREA 2.673000 ;
    PORT
      LAYER met2 ;
        RECT 1334.550 0.000 1334.830 4.000 ;
    END
  END s_core_o[23]
  PIN s_core_o[24]
    DIRECTION OUTPUT TRISTATE ;
    USE SIGNAL ;
    ANTENNADIFFAREA 2.673000 ;
    PORT
      LAYER met2 ;
        RECT 1348.810 0.000 1349.090 4.000 ;
    END
  END s_core_o[24]
  PIN s_core_o[25]
    DIRECTION OUTPUT TRISTATE ;
    USE SIGNAL ;
    ANTENNADIFFAREA 2.673000 ;
    PORT
      LAYER met2 ;
        RECT 1363.070 0.000 1363.350 4.000 ;
    END
  END s_core_o[25]
  PIN s_core_o[26]
    DIRECTION OUTPUT TRISTATE ;
    USE SIGNAL ;
    ANTENNADIFFAREA 2.673000 ;
    PORT
      LAYER met2 ;
        RECT 1377.330 0.000 1377.610 4.000 ;
    END
  END s_core_o[26]
  PIN s_core_o[27]
    DIRECTION OUTPUT TRISTATE ;
    USE SIGNAL ;
    ANTENNADIFFAREA 2.673000 ;
    PORT
      LAYER met2 ;
        RECT 1391.590 0.000 1391.870 4.000 ;
    END
  END s_core_o[27]
  PIN s_core_o[28]
    DIRECTION OUTPUT TRISTATE ;
    USE SIGNAL ;
    ANTENNADIFFAREA 2.673000 ;
    PORT
      LAYER met2 ;
        RECT 1405.850 0.000 1406.130 4.000 ;
    END
  END s_core_o[28]
  PIN s_core_o[29]
    DIRECTION OUTPUT TRISTATE ;
    USE SIGNAL ;
    ANTENNADIFFAREA 2.673000 ;
    PORT
      LAYER met2 ;
        RECT 1420.110 0.000 1420.390 4.000 ;
    END
  END s_core_o[29]
  PIN s_core_o[2]
    DIRECTION OUTPUT TRISTATE ;
    USE SIGNAL ;
    ANTENNADIFFAREA 2.673000 ;
    PORT
      LAYER met2 ;
        RECT 1035.090 0.000 1035.370 4.000 ;
    END
  END s_core_o[2]
  PIN s_core_o[30]
    DIRECTION OUTPUT TRISTATE ;
    USE SIGNAL ;
    ANTENNADIFFAREA 2.673000 ;
    PORT
      LAYER met2 ;
        RECT 1434.370 0.000 1434.650 4.000 ;
    END
  END s_core_o[30]
  PIN s_core_o[31]
    DIRECTION OUTPUT TRISTATE ;
    USE SIGNAL ;
    ANTENNADIFFAREA 2.673000 ;
    PORT
      LAYER met2 ;
        RECT 1448.630 0.000 1448.910 4.000 ;
    END
  END s_core_o[31]
  PIN s_core_o[32]
    DIRECTION OUTPUT TRISTATE ;
    USE SIGNAL ;
    ANTENNADIFFAREA 2.673000 ;
    PORT
      LAYER met2 ;
        RECT 1462.890 0.000 1463.170 4.000 ;
    END
  END s_core_o[32]
  PIN s_core_o[33]
    DIRECTION OUTPUT TRISTATE ;
    USE SIGNAL ;
    PORT
      LAYER met2 ;
        RECT 1477.150 0.000 1477.430 4.000 ;
    END
  END s_core_o[33]
  PIN s_core_o[3]
    DIRECTION OUTPUT TRISTATE ;
    USE SIGNAL ;
    ANTENNADIFFAREA 2.673000 ;
    PORT
      LAYER met2 ;
        RECT 1049.350 0.000 1049.630 4.000 ;
    END
  END s_core_o[3]
  PIN s_core_o[4]
    DIRECTION OUTPUT TRISTATE ;
    USE SIGNAL ;
    ANTENNADIFFAREA 2.673000 ;
    PORT
      LAYER met2 ;
        RECT 1063.610 0.000 1063.890 4.000 ;
    END
  END s_core_o[4]
  PIN s_core_o[5]
    DIRECTION OUTPUT TRISTATE ;
    USE SIGNAL ;
    ANTENNADIFFAREA 2.673000 ;
    PORT
      LAYER met2 ;
        RECT 1077.870 0.000 1078.150 4.000 ;
    END
  END s_core_o[5]
  PIN s_core_o[6]
    DIRECTION OUTPUT TRISTATE ;
    USE SIGNAL ;
    ANTENNADIFFAREA 2.673000 ;
    PORT
      LAYER met2 ;
        RECT 1092.130 0.000 1092.410 4.000 ;
    END
  END s_core_o[6]
  PIN s_core_o[7]
    DIRECTION OUTPUT TRISTATE ;
    USE SIGNAL ;
    ANTENNADIFFAREA 2.673000 ;
    PORT
      LAYER met2 ;
        RECT 1106.390 0.000 1106.670 4.000 ;
    END
  END s_core_o[7]
  PIN s_core_o[8]
    DIRECTION OUTPUT TRISTATE ;
    USE SIGNAL ;
    ANTENNADIFFAREA 2.673000 ;
    PORT
      LAYER met2 ;
        RECT 1120.650 0.000 1120.930 4.000 ;
    END
  END s_core_o[8]
  PIN s_core_o[9]
    DIRECTION OUTPUT TRISTATE ;
    USE SIGNAL ;
    ANTENNADIFFAREA 2.673000 ;
    PORT
      LAYER met2 ;
        RECT 1134.910 0.000 1135.190 4.000 ;
    END
  END s_core_o[9]
  PIN vccd1
    DIRECTION INOUT ;
    USE POWER ;
    PORT
      LAYER met2 ;
        RECT 21.040 10.640 22.640 1488.080 ;
    END
    PORT
      LAYER met2 ;
        RECT 174.640 10.640 176.240 1488.080 ;
    END
    PORT
      LAYER met2 ;
        RECT 328.240 10.640 329.840 1488.080 ;
    END
    PORT
      LAYER met2 ;
        RECT 481.840 10.640 483.440 1488.080 ;
    END
    PORT
      LAYER met2 ;
        RECT 635.440 10.640 637.040 589.720 ;
    END
    PORT
      LAYER met2 ;
        RECT 635.440 998.150 637.040 1488.080 ;
    END
    PORT
      LAYER met2 ;
        RECT 789.040 10.640 790.640 589.720 ;
    END
    PORT
      LAYER met2 ;
        RECT 789.040 998.150 790.640 1488.080 ;
    END
    PORT
      LAYER met2 ;
        RECT 942.640 10.640 944.240 1488.080 ;
    END
    PORT
      LAYER met2 ;
        RECT 1096.240 10.640 1097.840 1488.080 ;
    END
    PORT
      LAYER met2 ;
        RECT 1249.840 10.640 1251.440 1488.080 ;
    END
    PORT
      LAYER met2 ;
        RECT 1403.440 10.640 1405.040 1488.080 ;
    END
    PORT
      LAYER met3 ;
        RECT 5.280 26.730 1494.320 28.330 ;
    END
    PORT
      LAYER met3 ;
        RECT 5.280 179.910 1494.320 181.510 ;
    END
    PORT
      LAYER met3 ;
        RECT 5.280 333.090 1494.320 334.690 ;
    END
    PORT
      LAYER met3 ;
        RECT 5.280 486.270 1494.320 487.870 ;
    END
    PORT
      LAYER met3 ;
        RECT 5.280 639.450 1494.320 641.050 ;
    END
    PORT
      LAYER met3 ;
        RECT 5.280 792.630 589.400 794.230 ;
    END
    PORT
      LAYER met3 ;
        RECT 5.280 945.810 1494.320 947.410 ;
    END
    PORT
      LAYER met3 ;
        RECT 5.280 1098.990 1494.320 1100.590 ;
    END
    PORT
      LAYER met3 ;
        RECT 5.280 1252.170 1494.320 1253.770 ;
    END
    PORT
      LAYER met3 ;
        RECT 5.280 1405.350 1494.320 1406.950 ;
    END
    PORT
      LAYER met3 ;
        RECT 915.190 792.630 1494.320 794.230 ;
    END
  END vccd1
  PIN vssd1
    DIRECTION INOUT ;
    USE GROUND ;
    PORT
      LAYER met2 ;
        RECT 24.340 10.640 25.940 1488.080 ;
    END
    PORT
      LAYER met2 ;
        RECT 177.940 10.640 179.540 1488.080 ;
    END
    PORT
      LAYER met2 ;
        RECT 331.540 10.640 333.140 1488.080 ;
    END
    PORT
      LAYER met2 ;
        RECT 485.140 10.640 486.740 1488.080 ;
    END
    PORT
      LAYER met2 ;
        RECT 638.740 10.640 640.340 589.720 ;
    END
    PORT
      LAYER met2 ;
        RECT 638.740 998.150 640.340 1488.080 ;
    END
    PORT
      LAYER met2 ;
        RECT 792.340 10.640 793.940 589.720 ;
    END
    PORT
      LAYER met2 ;
        RECT 792.340 998.150 793.940 1488.080 ;
    END
    PORT
      LAYER met2 ;
        RECT 945.940 10.640 947.540 1488.080 ;
    END
    PORT
      LAYER met2 ;
        RECT 1099.540 10.640 1101.140 1488.080 ;
    END
    PORT
      LAYER met2 ;
        RECT 1253.140 10.640 1254.740 1488.080 ;
    END
    PORT
      LAYER met2 ;
        RECT 1406.740 10.640 1408.340 1488.080 ;
    END
    PORT
      LAYER met3 ;
        RECT 5.280 30.030 1494.320 31.630 ;
    END
    PORT
      LAYER met3 ;
        RECT 5.280 183.210 1494.320 184.810 ;
    END
    PORT
      LAYER met3 ;
        RECT 5.280 336.390 1494.320 337.990 ;
    END
    PORT
      LAYER met3 ;
        RECT 5.280 489.570 1494.320 491.170 ;
    END
    PORT
      LAYER met3 ;
        RECT 5.280 642.750 1494.320 644.350 ;
    END
    PORT
      LAYER met3 ;
        RECT 5.280 795.930 589.400 797.530 ;
    END
    PORT
      LAYER met3 ;
        RECT 5.280 949.110 1494.320 950.710 ;
    END
    PORT
      LAYER met3 ;
        RECT 5.280 1102.290 1494.320 1103.890 ;
    END
    PORT
      LAYER met3 ;
        RECT 5.280 1255.470 1494.320 1257.070 ;
    END
    PORT
      LAYER met3 ;
        RECT 5.280 1408.650 1494.320 1410.250 ;
    END
    PORT
      LAYER met3 ;
        RECT 915.190 795.930 1494.320 797.530 ;
    END
  END vssd1
  OBS
      LAYER li1 ;
        RECT 5.520 10.795 1494.080 1487.925 ;
      LAYER met1 ;
        RECT 5.520 9.900 1495.390 1488.080 ;
      LAYER met2 ;
        RECT 22.700 1495.720 374.710 1496.000 ;
        RECT 375.550 1495.720 1124.510 1496.000 ;
        RECT 1125.350 1495.720 1495.370 1496.000 ;
        RECT 22.700 1488.360 1495.370 1495.720 ;
        RECT 22.920 10.360 24.060 1488.360 ;
        RECT 26.220 10.360 174.360 1488.360 ;
        RECT 176.520 10.360 177.660 1488.360 ;
        RECT 179.820 10.360 327.960 1488.360 ;
        RECT 330.120 10.360 331.260 1488.360 ;
        RECT 333.420 10.360 481.560 1488.360 ;
        RECT 483.720 10.360 484.860 1488.360 ;
        RECT 487.020 997.870 635.160 1488.360 ;
        RECT 637.320 997.870 638.460 1488.360 ;
        RECT 640.620 997.870 788.760 1488.360 ;
        RECT 790.920 997.870 792.060 1488.360 ;
        RECT 794.220 997.870 942.360 1488.360 ;
        RECT 487.020 590.000 942.360 997.870 ;
        RECT 487.020 10.360 635.160 590.000 ;
        RECT 637.320 10.360 638.460 590.000 ;
        RECT 640.620 10.360 788.760 590.000 ;
        RECT 790.920 10.360 792.060 590.000 ;
        RECT 794.220 10.360 942.360 590.000 ;
        RECT 944.520 10.360 945.660 1488.360 ;
        RECT 947.820 10.360 1095.960 1488.360 ;
        RECT 1098.120 10.360 1099.260 1488.360 ;
        RECT 1101.420 10.360 1249.560 1488.360 ;
        RECT 1251.720 10.360 1252.860 1488.360 ;
        RECT 1255.020 10.360 1403.160 1488.360 ;
        RECT 1405.320 10.360 1406.460 1488.360 ;
        RECT 1408.620 10.360 1495.370 1488.360 ;
        RECT 22.700 4.280 1495.370 10.360 ;
        RECT 23.190 3.670 36.610 4.280 ;
        RECT 37.450 3.670 50.870 4.280 ;
        RECT 51.710 3.670 65.130 4.280 ;
        RECT 65.970 3.670 79.390 4.280 ;
        RECT 80.230 3.670 93.650 4.280 ;
        RECT 94.490 3.670 107.910 4.280 ;
        RECT 108.750 3.670 122.170 4.280 ;
        RECT 123.010 3.670 136.430 4.280 ;
        RECT 137.270 3.670 150.690 4.280 ;
        RECT 151.530 3.670 164.950 4.280 ;
        RECT 165.790 3.670 179.210 4.280 ;
        RECT 180.050 3.670 193.470 4.280 ;
        RECT 194.310 3.670 207.730 4.280 ;
        RECT 208.570 3.670 221.990 4.280 ;
        RECT 222.830 3.670 236.250 4.280 ;
        RECT 237.090 3.670 250.510 4.280 ;
        RECT 251.350 3.670 264.770 4.280 ;
        RECT 265.610 3.670 279.030 4.280 ;
        RECT 279.870 3.670 293.290 4.280 ;
        RECT 294.130 3.670 307.550 4.280 ;
        RECT 308.390 3.670 321.810 4.280 ;
        RECT 322.650 3.670 336.070 4.280 ;
        RECT 336.910 3.670 350.330 4.280 ;
        RECT 351.170 3.670 364.590 4.280 ;
        RECT 365.430 3.670 378.850 4.280 ;
        RECT 379.690 3.670 393.110 4.280 ;
        RECT 393.950 3.670 407.370 4.280 ;
        RECT 408.210 3.670 421.630 4.280 ;
        RECT 422.470 3.670 435.890 4.280 ;
        RECT 436.730 3.670 450.150 4.280 ;
        RECT 450.990 3.670 464.410 4.280 ;
        RECT 465.250 3.670 478.670 4.280 ;
        RECT 479.510 3.670 492.930 4.280 ;
        RECT 493.770 3.670 507.190 4.280 ;
        RECT 508.030 3.670 521.450 4.280 ;
        RECT 522.290 3.670 535.710 4.280 ;
        RECT 536.550 3.670 549.970 4.280 ;
        RECT 550.810 3.670 564.230 4.280 ;
        RECT 565.070 3.670 578.490 4.280 ;
        RECT 579.330 3.670 592.750 4.280 ;
        RECT 593.590 3.670 607.010 4.280 ;
        RECT 607.850 3.670 621.270 4.280 ;
        RECT 622.110 3.670 635.530 4.280 ;
        RECT 636.370 3.670 649.790 4.280 ;
        RECT 650.630 3.670 664.050 4.280 ;
        RECT 664.890 3.670 678.310 4.280 ;
        RECT 679.150 3.670 692.570 4.280 ;
        RECT 693.410 3.670 706.830 4.280 ;
        RECT 707.670 3.670 721.090 4.280 ;
        RECT 721.930 3.670 735.350 4.280 ;
        RECT 736.190 3.670 749.610 4.280 ;
        RECT 750.450 3.670 763.870 4.280 ;
        RECT 764.710 3.670 778.130 4.280 ;
        RECT 778.970 3.670 792.390 4.280 ;
        RECT 793.230 3.670 806.650 4.280 ;
        RECT 807.490 3.670 820.910 4.280 ;
        RECT 821.750 3.670 835.170 4.280 ;
        RECT 836.010 3.670 849.430 4.280 ;
        RECT 850.270 3.670 863.690 4.280 ;
        RECT 864.530 3.670 877.950 4.280 ;
        RECT 878.790 3.670 892.210 4.280 ;
        RECT 893.050 3.670 906.470 4.280 ;
        RECT 907.310 3.670 920.730 4.280 ;
        RECT 921.570 3.670 934.990 4.280 ;
        RECT 935.830 3.670 949.250 4.280 ;
        RECT 950.090 3.670 963.510 4.280 ;
        RECT 964.350 3.670 977.770 4.280 ;
        RECT 978.610 3.670 992.030 4.280 ;
        RECT 992.870 3.670 1006.290 4.280 ;
        RECT 1007.130 3.670 1020.550 4.280 ;
        RECT 1021.390 3.670 1034.810 4.280 ;
        RECT 1035.650 3.670 1049.070 4.280 ;
        RECT 1049.910 3.670 1063.330 4.280 ;
        RECT 1064.170 3.670 1077.590 4.280 ;
        RECT 1078.430 3.670 1091.850 4.280 ;
        RECT 1092.690 3.670 1106.110 4.280 ;
        RECT 1106.950 3.670 1120.370 4.280 ;
        RECT 1121.210 3.670 1134.630 4.280 ;
        RECT 1135.470 3.670 1148.890 4.280 ;
        RECT 1149.730 3.670 1163.150 4.280 ;
        RECT 1163.990 3.670 1177.410 4.280 ;
        RECT 1178.250 3.670 1191.670 4.280 ;
        RECT 1192.510 3.670 1205.930 4.280 ;
        RECT 1206.770 3.670 1220.190 4.280 ;
        RECT 1221.030 3.670 1234.450 4.280 ;
        RECT 1235.290 3.670 1248.710 4.280 ;
        RECT 1249.550 3.670 1262.970 4.280 ;
        RECT 1263.810 3.670 1277.230 4.280 ;
        RECT 1278.070 3.670 1291.490 4.280 ;
        RECT 1292.330 3.670 1305.750 4.280 ;
        RECT 1306.590 3.670 1320.010 4.280 ;
        RECT 1320.850 3.670 1334.270 4.280 ;
        RECT 1335.110 3.670 1348.530 4.280 ;
        RECT 1349.370 3.670 1362.790 4.280 ;
        RECT 1363.630 3.670 1377.050 4.280 ;
        RECT 1377.890 3.670 1391.310 4.280 ;
        RECT 1392.150 3.670 1405.570 4.280 ;
        RECT 1406.410 3.670 1419.830 4.280 ;
        RECT 1420.670 3.670 1434.090 4.280 ;
        RECT 1434.930 3.670 1448.350 4.280 ;
        RECT 1449.190 3.670 1462.610 4.280 ;
        RECT 1463.450 3.670 1476.870 4.280 ;
        RECT 1477.710 3.670 1495.370 4.280 ;
      LAYER met3 ;
        RECT 384.165 1442.600 1495.600 1443.465 ;
        RECT 384.165 1430.400 1496.000 1442.600 ;
        RECT 384.165 1429.000 1495.600 1430.400 ;
        RECT 384.165 1416.800 1496.000 1429.000 ;
        RECT 384.165 1415.400 1495.600 1416.800 ;
        RECT 384.165 1410.650 1496.000 1415.400 ;
        RECT 1494.720 1408.250 1496.000 1410.650 ;
        RECT 384.165 1407.350 1496.000 1408.250 ;
        RECT 1494.720 1404.950 1496.000 1407.350 ;
        RECT 384.165 1403.200 1496.000 1404.950 ;
        RECT 384.165 1401.800 1495.600 1403.200 ;
        RECT 384.165 1389.600 1496.000 1401.800 ;
        RECT 384.165 1388.200 1495.600 1389.600 ;
        RECT 384.165 1376.000 1496.000 1388.200 ;
        RECT 384.165 1374.600 1495.600 1376.000 ;
        RECT 384.165 1362.400 1496.000 1374.600 ;
        RECT 384.165 1361.000 1495.600 1362.400 ;
        RECT 384.165 1348.800 1496.000 1361.000 ;
        RECT 384.165 1347.400 1495.600 1348.800 ;
        RECT 384.165 1335.200 1496.000 1347.400 ;
        RECT 384.165 1333.800 1495.600 1335.200 ;
        RECT 384.165 1321.600 1496.000 1333.800 ;
        RECT 384.165 1320.200 1495.600 1321.600 ;
        RECT 384.165 1308.000 1496.000 1320.200 ;
        RECT 384.165 1306.600 1495.600 1308.000 ;
        RECT 384.165 1294.400 1496.000 1306.600 ;
        RECT 384.165 1293.000 1495.600 1294.400 ;
        RECT 384.165 1280.800 1496.000 1293.000 ;
        RECT 384.165 1279.400 1495.600 1280.800 ;
        RECT 384.165 1267.200 1496.000 1279.400 ;
        RECT 384.165 1265.800 1495.600 1267.200 ;
        RECT 384.165 1257.470 1496.000 1265.800 ;
        RECT 1494.720 1255.070 1496.000 1257.470 ;
        RECT 384.165 1254.170 1496.000 1255.070 ;
        RECT 1494.720 1253.600 1496.000 1254.170 ;
        RECT 1494.720 1252.200 1495.600 1253.600 ;
        RECT 1494.720 1251.770 1496.000 1252.200 ;
        RECT 384.165 1240.000 1496.000 1251.770 ;
        RECT 384.165 1238.600 1495.600 1240.000 ;
        RECT 384.165 1226.400 1496.000 1238.600 ;
        RECT 384.165 1225.000 1495.600 1226.400 ;
        RECT 384.165 1212.800 1496.000 1225.000 ;
        RECT 384.165 1211.400 1495.600 1212.800 ;
        RECT 384.165 1199.200 1496.000 1211.400 ;
        RECT 384.165 1197.800 1495.600 1199.200 ;
        RECT 384.165 1185.600 1496.000 1197.800 ;
        RECT 384.165 1184.200 1495.600 1185.600 ;
        RECT 384.165 1172.000 1496.000 1184.200 ;
        RECT 384.165 1170.600 1495.600 1172.000 ;
        RECT 384.165 1158.400 1496.000 1170.600 ;
        RECT 384.165 1157.000 1495.600 1158.400 ;
        RECT 384.165 1144.800 1496.000 1157.000 ;
        RECT 384.165 1143.400 1495.600 1144.800 ;
        RECT 384.165 1131.200 1496.000 1143.400 ;
        RECT 384.165 1129.800 1495.600 1131.200 ;
        RECT 384.165 1117.600 1496.000 1129.800 ;
        RECT 384.165 1116.200 1495.600 1117.600 ;
        RECT 384.165 1104.290 1496.000 1116.200 ;
        RECT 1494.720 1104.000 1496.000 1104.290 ;
        RECT 1494.720 1102.600 1495.600 1104.000 ;
        RECT 1494.720 1101.890 1496.000 1102.600 ;
        RECT 384.165 1100.990 1496.000 1101.890 ;
        RECT 1494.720 1098.590 1496.000 1100.990 ;
        RECT 384.165 1090.400 1496.000 1098.590 ;
        RECT 384.165 1089.000 1495.600 1090.400 ;
        RECT 384.165 1076.800 1496.000 1089.000 ;
        RECT 384.165 1075.400 1495.600 1076.800 ;
        RECT 384.165 1063.200 1496.000 1075.400 ;
        RECT 384.165 1061.800 1495.600 1063.200 ;
        RECT 384.165 1049.600 1496.000 1061.800 ;
        RECT 384.165 1048.200 1495.600 1049.600 ;
        RECT 384.165 1036.000 1496.000 1048.200 ;
        RECT 384.165 1034.600 1495.600 1036.000 ;
        RECT 384.165 1022.400 1496.000 1034.600 ;
        RECT 384.165 1021.000 1495.600 1022.400 ;
        RECT 384.165 1008.800 1496.000 1021.000 ;
        RECT 384.165 1007.400 1495.600 1008.800 ;
        RECT 384.165 995.200 1496.000 1007.400 ;
        RECT 384.165 993.800 1495.600 995.200 ;
        RECT 384.165 981.600 1496.000 993.800 ;
        RECT 384.165 980.200 1495.600 981.600 ;
        RECT 384.165 968.000 1496.000 980.200 ;
        RECT 384.165 966.600 1495.600 968.000 ;
        RECT 384.165 954.400 1496.000 966.600 ;
        RECT 384.165 953.000 1495.600 954.400 ;
        RECT 384.165 951.110 1496.000 953.000 ;
        RECT 1494.720 948.710 1496.000 951.110 ;
        RECT 384.165 947.810 1496.000 948.710 ;
        RECT 1494.720 945.410 1496.000 947.810 ;
        RECT 384.165 940.800 1496.000 945.410 ;
        RECT 384.165 939.400 1495.600 940.800 ;
        RECT 384.165 927.200 1496.000 939.400 ;
        RECT 384.165 925.800 1495.600 927.200 ;
        RECT 384.165 913.600 1496.000 925.800 ;
        RECT 384.165 912.200 1495.600 913.600 ;
        RECT 384.165 900.000 1496.000 912.200 ;
        RECT 384.165 898.600 1495.600 900.000 ;
        RECT 384.165 886.400 1496.000 898.600 ;
        RECT 384.165 885.000 1495.600 886.400 ;
        RECT 384.165 872.800 1496.000 885.000 ;
        RECT 384.165 871.400 1495.600 872.800 ;
        RECT 384.165 859.200 1496.000 871.400 ;
        RECT 384.165 857.800 1495.600 859.200 ;
        RECT 384.165 845.600 1496.000 857.800 ;
        RECT 384.165 844.200 1495.600 845.600 ;
        RECT 384.165 832.000 1496.000 844.200 ;
        RECT 384.165 830.600 1495.600 832.000 ;
        RECT 384.165 818.400 1496.000 830.600 ;
        RECT 384.165 817.000 1495.600 818.400 ;
        RECT 384.165 804.800 1496.000 817.000 ;
        RECT 384.165 803.400 1495.600 804.800 ;
        RECT 384.165 797.930 1496.000 803.400 ;
        RECT 589.800 795.530 914.790 797.930 ;
        RECT 1494.720 795.530 1496.000 797.930 ;
        RECT 384.165 794.630 1496.000 795.530 ;
        RECT 589.800 792.230 914.790 794.630 ;
        RECT 1494.720 792.230 1496.000 794.630 ;
        RECT 384.165 791.200 1496.000 792.230 ;
        RECT 384.165 789.800 1495.600 791.200 ;
        RECT 384.165 777.600 1496.000 789.800 ;
        RECT 384.165 776.200 1495.600 777.600 ;
        RECT 384.165 764.000 1496.000 776.200 ;
        RECT 384.165 762.600 1495.600 764.000 ;
        RECT 384.165 750.400 1496.000 762.600 ;
        RECT 384.165 749.000 1495.600 750.400 ;
        RECT 384.165 736.800 1496.000 749.000 ;
        RECT 384.165 735.400 1495.600 736.800 ;
        RECT 384.165 723.200 1496.000 735.400 ;
        RECT 384.165 721.800 1495.600 723.200 ;
        RECT 384.165 709.600 1496.000 721.800 ;
        RECT 384.165 708.200 1495.600 709.600 ;
        RECT 384.165 696.000 1496.000 708.200 ;
        RECT 384.165 694.600 1495.600 696.000 ;
        RECT 384.165 682.400 1496.000 694.600 ;
        RECT 384.165 681.000 1495.600 682.400 ;
        RECT 384.165 668.800 1496.000 681.000 ;
        RECT 384.165 667.400 1495.600 668.800 ;
        RECT 384.165 655.200 1496.000 667.400 ;
        RECT 384.165 653.800 1495.600 655.200 ;
        RECT 384.165 644.750 1496.000 653.800 ;
        RECT 1494.720 642.350 1496.000 644.750 ;
        RECT 384.165 641.600 1496.000 642.350 ;
        RECT 384.165 641.450 1495.600 641.600 ;
        RECT 1494.720 640.200 1495.600 641.450 ;
        RECT 1494.720 639.050 1496.000 640.200 ;
        RECT 384.165 628.000 1496.000 639.050 ;
        RECT 384.165 626.600 1495.600 628.000 ;
        RECT 384.165 614.400 1496.000 626.600 ;
        RECT 384.165 613.000 1495.600 614.400 ;
        RECT 384.165 600.800 1496.000 613.000 ;
        RECT 384.165 599.400 1495.600 600.800 ;
        RECT 384.165 587.200 1496.000 599.400 ;
        RECT 384.165 585.800 1495.600 587.200 ;
        RECT 384.165 573.600 1496.000 585.800 ;
        RECT 384.165 572.200 1495.600 573.600 ;
        RECT 384.165 560.000 1496.000 572.200 ;
        RECT 384.165 558.600 1495.600 560.000 ;
        RECT 384.165 546.400 1496.000 558.600 ;
        RECT 384.165 545.000 1495.600 546.400 ;
        RECT 384.165 532.800 1496.000 545.000 ;
        RECT 384.165 531.400 1495.600 532.800 ;
        RECT 384.165 519.200 1496.000 531.400 ;
        RECT 384.165 517.800 1495.600 519.200 ;
        RECT 384.165 505.600 1496.000 517.800 ;
        RECT 384.165 504.200 1495.600 505.600 ;
        RECT 384.165 492.000 1496.000 504.200 ;
        RECT 384.165 491.570 1495.600 492.000 ;
        RECT 1494.720 490.600 1495.600 491.570 ;
        RECT 1494.720 489.170 1496.000 490.600 ;
        RECT 384.165 488.270 1496.000 489.170 ;
        RECT 1494.720 485.870 1496.000 488.270 ;
        RECT 384.165 478.400 1496.000 485.870 ;
        RECT 384.165 477.000 1495.600 478.400 ;
        RECT 384.165 464.800 1496.000 477.000 ;
        RECT 384.165 463.400 1495.600 464.800 ;
        RECT 384.165 451.200 1496.000 463.400 ;
        RECT 384.165 449.800 1495.600 451.200 ;
        RECT 384.165 437.600 1496.000 449.800 ;
        RECT 384.165 436.200 1495.600 437.600 ;
        RECT 384.165 424.000 1496.000 436.200 ;
        RECT 384.165 422.600 1495.600 424.000 ;
        RECT 384.165 410.400 1496.000 422.600 ;
        RECT 384.165 409.000 1495.600 410.400 ;
        RECT 384.165 396.800 1496.000 409.000 ;
        RECT 384.165 395.400 1495.600 396.800 ;
        RECT 384.165 383.200 1496.000 395.400 ;
        RECT 384.165 381.800 1495.600 383.200 ;
        RECT 384.165 369.600 1496.000 381.800 ;
        RECT 384.165 368.200 1495.600 369.600 ;
        RECT 384.165 356.000 1496.000 368.200 ;
        RECT 384.165 354.600 1495.600 356.000 ;
        RECT 384.165 342.400 1496.000 354.600 ;
        RECT 384.165 341.000 1495.600 342.400 ;
        RECT 384.165 338.390 1496.000 341.000 ;
        RECT 1494.720 335.990 1496.000 338.390 ;
        RECT 384.165 335.090 1496.000 335.990 ;
        RECT 1494.720 332.690 1496.000 335.090 ;
        RECT 384.165 328.800 1496.000 332.690 ;
        RECT 384.165 327.400 1495.600 328.800 ;
        RECT 384.165 315.200 1496.000 327.400 ;
        RECT 384.165 313.800 1495.600 315.200 ;
        RECT 384.165 301.600 1496.000 313.800 ;
        RECT 384.165 300.200 1495.600 301.600 ;
        RECT 384.165 288.000 1496.000 300.200 ;
        RECT 384.165 286.600 1495.600 288.000 ;
        RECT 384.165 274.400 1496.000 286.600 ;
        RECT 384.165 273.000 1495.600 274.400 ;
        RECT 384.165 260.800 1496.000 273.000 ;
        RECT 384.165 259.400 1495.600 260.800 ;
        RECT 384.165 247.200 1496.000 259.400 ;
        RECT 384.165 245.800 1495.600 247.200 ;
        RECT 384.165 233.600 1496.000 245.800 ;
        RECT 384.165 232.200 1495.600 233.600 ;
        RECT 384.165 220.000 1496.000 232.200 ;
        RECT 384.165 218.600 1495.600 220.000 ;
        RECT 384.165 206.400 1496.000 218.600 ;
        RECT 384.165 205.000 1495.600 206.400 ;
        RECT 384.165 192.800 1496.000 205.000 ;
        RECT 384.165 191.400 1495.600 192.800 ;
        RECT 384.165 185.210 1496.000 191.400 ;
        RECT 1494.720 182.810 1496.000 185.210 ;
        RECT 384.165 181.910 1496.000 182.810 ;
        RECT 1494.720 179.510 1496.000 181.910 ;
        RECT 384.165 179.200 1496.000 179.510 ;
        RECT 384.165 177.800 1495.600 179.200 ;
        RECT 384.165 165.600 1496.000 177.800 ;
        RECT 384.165 164.200 1495.600 165.600 ;
        RECT 384.165 152.000 1496.000 164.200 ;
        RECT 384.165 150.600 1495.600 152.000 ;
        RECT 384.165 138.400 1496.000 150.600 ;
        RECT 384.165 137.000 1495.600 138.400 ;
        RECT 384.165 124.800 1496.000 137.000 ;
        RECT 384.165 123.400 1495.600 124.800 ;
        RECT 384.165 111.200 1496.000 123.400 ;
        RECT 384.165 109.800 1495.600 111.200 ;
        RECT 384.165 97.600 1496.000 109.800 ;
        RECT 384.165 96.200 1495.600 97.600 ;
        RECT 384.165 84.000 1496.000 96.200 ;
        RECT 384.165 82.600 1495.600 84.000 ;
        RECT 384.165 70.400 1496.000 82.600 ;
        RECT 384.165 69.000 1495.600 70.400 ;
        RECT 384.165 56.800 1496.000 69.000 ;
        RECT 384.165 55.935 1495.600 56.800 ;
      LAYER met4 ;
        RECT 740.895 61.375 1403.625 969.505 ;
  END
END metadata_cache_m
END LIBRARY

